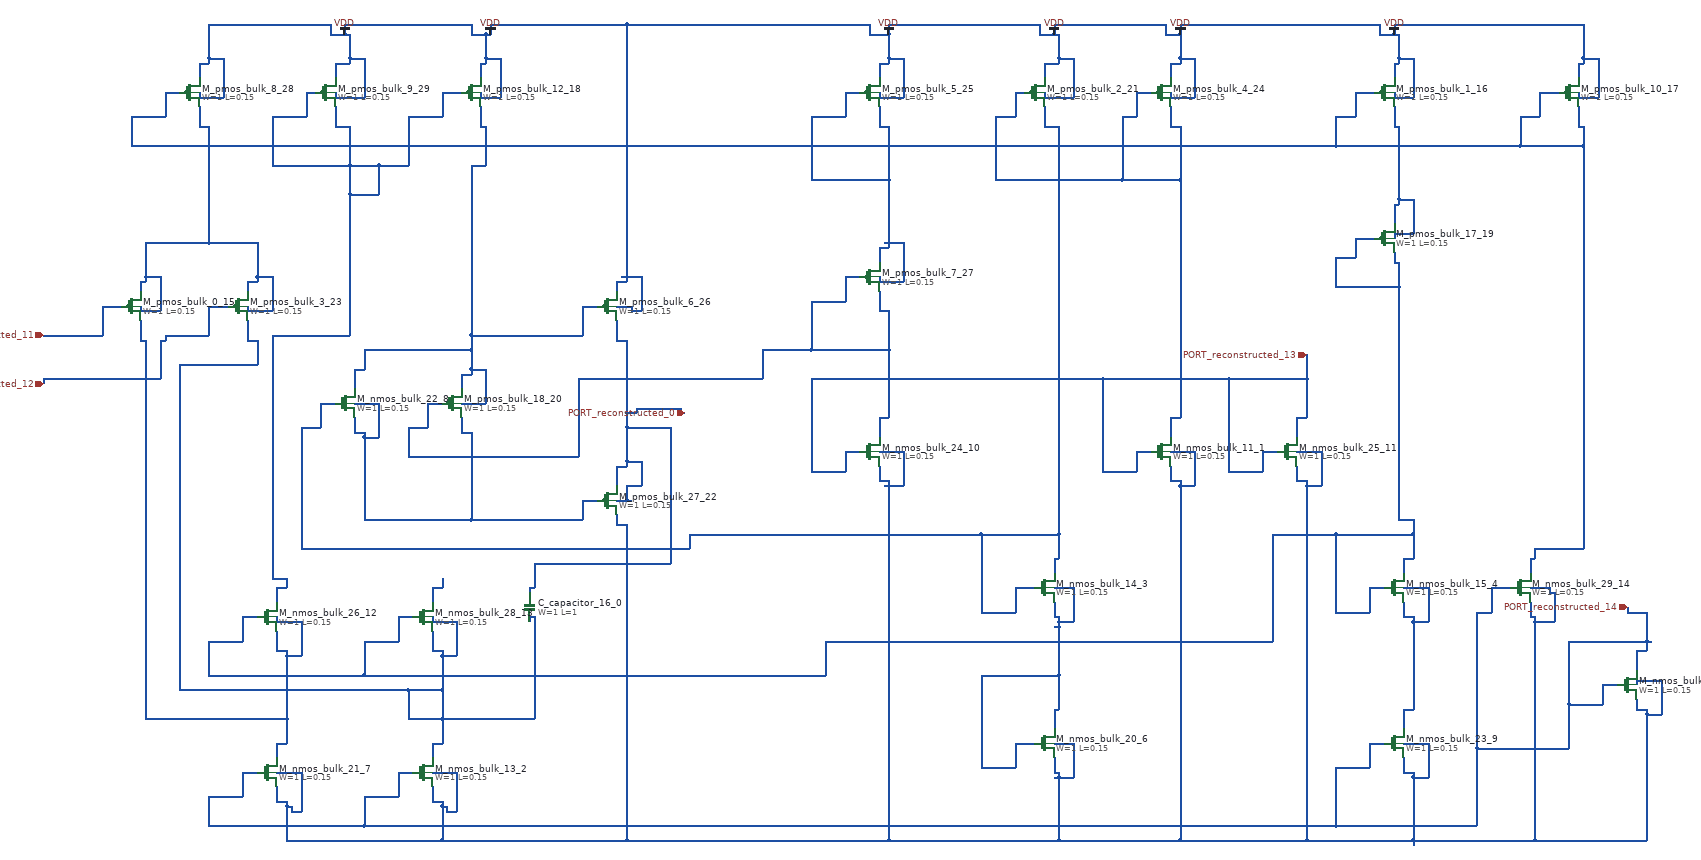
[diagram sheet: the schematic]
v {xschem version=3.4.8 file_version=1.2}
G {}
K {}
V {}
S {}
E {}
C {sky130_fd_pr/cap_mim_m3_1.sym} 1160 1220 2 0 {name="C_capacitor_16_0" model=cap_mim_m3_1 W=1 L=1 MF=1 spiceprefix=X}
C {sky130_fd_pr/nfet_01v8.sym} 2460 900 0 0 {name="M_nmos_bulk_11_1"
W=1
L=0.15
nf=1 
mult=1
ad="expr('int((@nf + 1)/2) * @W / @nf * 0.29')"
pd="expr('2*int((@nf + 1)/2) * (@W / @nf + 0.29)')"
as="expr('int((@nf + 2)/2) * @W / @nf * 0.29')"
ps="expr('2*int((@nf + 2)/2) * (@W / @nf + 0.29)')"
nrd="expr('0.29 / @W ')" nrs="expr('0.29 / @W ')"
sa=0 sb=0 sd=0
model=nfet_01v8
spiceprefix=X
}
C {sky130_fd_pr/nfet_01v8.sym} 940 1560 0 0 {name="M_nmos_bulk_13_2"
W=1
L=0.15
nf=1 
mult=1
ad="expr('int((@nf + 1)/2) * @W / @nf * 0.29')"
pd="expr('2*int((@nf + 1)/2) * (@W / @nf + 0.29)')"
as="expr('int((@nf + 2)/2) * @W / @nf * 0.29')"
ps="expr('2*int((@nf + 2)/2) * (@W / @nf + 0.29)')"
nrd="expr('0.29 / @W ')" nrs="expr('0.29 / @W ')"
sa=0 sb=0 sd=0
model=nfet_01v8
spiceprefix=X
}
C {sky130_fd_pr/nfet_01v8.sym} 2220 1180 0 0 {name="M_nmos_bulk_14_3"
W=1
L=0.15
nf=1 
mult=1
ad="expr('int((@nf + 1)/2) * @W / @nf * 0.29')"
pd="expr('2*int((@nf + 1)/2) * (@W / @nf + 0.29)')"
as="expr('int((@nf + 2)/2) * @W / @nf * 0.29')"
ps="expr('2*int((@nf + 2)/2) * (@W / @nf + 0.29)')"
nrd="expr('0.29 / @W ')" nrs="expr('0.29 / @W ')"
sa=0 sb=0 sd=0
model=nfet_01v8
spiceprefix=X
}
C {sky130_fd_pr/nfet_01v8.sym} 2940 1180 0 0 {name="M_nmos_bulk_15_4"
W=1
L=0.15
nf=1 
mult=1
ad="expr('int((@nf + 1)/2) * @W / @nf * 0.29')"
pd="expr('2*int((@nf + 1)/2) * (@W / @nf + 0.29)')"
as="expr('int((@nf + 2)/2) * @W / @nf * 0.29')"
ps="expr('2*int((@nf + 2)/2) * (@W / @nf + 0.29)')"
nrd="expr('0.29 / @W ')" nrs="expr('0.29 / @W ')"
sa=0 sb=0 sd=0
model=nfet_01v8
spiceprefix=X
}
C {sky130_fd_pr/nfet_01v8.sym} 3420 1380 0 0 {name="M_nmos_bulk_19_5"
W=1
L=0.15
nf=1 
mult=1
ad="expr('int((@nf + 1)/2) * @W / @nf * 0.29')"
pd="expr('2*int((@nf + 1)/2) * (@W / @nf + 0.29)')"
as="expr('int((@nf + 2)/2) * @W / @nf * 0.29')"
ps="expr('2*int((@nf + 2)/2) * (@W / @nf + 0.29)')"
nrd="expr('0.29 / @W ')" nrs="expr('0.29 / @W ')"
sa=0 sb=0 sd=0
model=nfet_01v8
spiceprefix=X
}
C {sky130_fd_pr/nfet_01v8.sym} 2220 1500 0 0 {name="M_nmos_bulk_20_6"
W=1
L=0.15
nf=1 
mult=1
ad="expr('int((@nf + 1)/2) * @W / @nf * 0.29')"
pd="expr('2*int((@nf + 1)/2) * (@W / @nf + 0.29)')"
as="expr('int((@nf + 2)/2) * @W / @nf * 0.29')"
ps="expr('2*int((@nf + 2)/2) * (@W / @nf + 0.29)')"
nrd="expr('0.29 / @W ')" nrs="expr('0.29 / @W ')"
sa=0 sb=0 sd=0
model=nfet_01v8
spiceprefix=X
}
C {sky130_fd_pr/nfet_01v8.sym} 620 1560 0 0 {name="M_nmos_bulk_21_7"
W=1
L=0.15
nf=1 
mult=1
ad="expr('int((@nf + 1)/2) * @W / @nf * 0.29')"
pd="expr('2*int((@nf + 1)/2) * (@W / @nf + 0.29)')"
as="expr('int((@nf + 2)/2) * @W / @nf * 0.29')"
ps="expr('2*int((@nf + 2)/2) * (@W / @nf + 0.29)')"
nrd="expr('0.29 / @W ')" nrs="expr('0.29 / @W ')"
sa=0 sb=0 sd=0
model=nfet_01v8
spiceprefix=X
}
C {sky130_fd_pr/nfet_01v8.sym} 780 800 0 0 {name="M_nmos_bulk_22_8"
W=1
L=0.15
nf=1 
mult=1
ad="expr('int((@nf + 1)/2) * @W / @nf * 0.29')"
pd="expr('2*int((@nf + 1)/2) * (@W / @nf + 0.29)')"
as="expr('int((@nf + 2)/2) * @W / @nf * 0.29')"
ps="expr('2*int((@nf + 2)/2) * (@W / @nf + 0.29)')"
nrd="expr('0.29 / @W ')" nrs="expr('0.29 / @W ')"
sa=0 sb=0 sd=0
model=nfet_01v8
spiceprefix=X
}
C {sky130_fd_pr/nfet_01v8.sym} 2940 1500 0 0 {name="M_nmos_bulk_23_9"
W=1
L=0.15
nf=1 
mult=1
ad="expr('int((@nf + 1)/2) * @W / @nf * 0.29')"
pd="expr('2*int((@nf + 1)/2) * (@W / @nf + 0.29)')"
as="expr('int((@nf + 2)/2) * @W / @nf * 0.29')"
ps="expr('2*int((@nf + 2)/2) * (@W / @nf + 0.29)')"
nrd="expr('0.29 / @W ')" nrs="expr('0.29 / @W ')"
sa=0 sb=0 sd=0
model=nfet_01v8
spiceprefix=X
}
C {sky130_fd_pr/nfet_01v8.sym} 1860 900 0 0 {name="M_nmos_bulk_24_10"
W=1
L=0.15
nf=1 
mult=1
ad="expr('int((@nf + 1)/2) * @W / @nf * 0.29')"
pd="expr('2*int((@nf + 1)/2) * (@W / @nf + 0.29)')"
as="expr('int((@nf + 2)/2) * @W / @nf * 0.29')"
ps="expr('2*int((@nf + 2)/2) * (@W / @nf + 0.29)')"
nrd="expr('0.29 / @W ')" nrs="expr('0.29 / @W ')"
sa=0 sb=0 sd=0
model=nfet_01v8
spiceprefix=X
}
C {sky130_fd_pr/nfet_01v8.sym} 2720 900 0 0 {name="M_nmos_bulk_25_11"
W=1
L=0.15
nf=1 
mult=1
ad="expr('int((@nf + 1)/2) * @W / @nf * 0.29')"
pd="expr('2*int((@nf + 1)/2) * (@W / @nf + 0.29)')"
as="expr('int((@nf + 2)/2) * @W / @nf * 0.29')"
ps="expr('2*int((@nf + 2)/2) * (@W / @nf + 0.29)')"
nrd="expr('0.29 / @W ')" nrs="expr('0.29 / @W ')"
sa=0 sb=0 sd=0
model=nfet_01v8
spiceprefix=X
}
C {sky130_fd_pr/nfet_01v8.sym} 620 1240 0 0 {name="M_nmos_bulk_26_12"
W=1
L=0.15
nf=1 
mult=1
ad="expr('int((@nf + 1)/2) * @W / @nf * 0.29')"
pd="expr('2*int((@nf + 1)/2) * (@W / @nf + 0.29)')"
as="expr('int((@nf + 2)/2) * @W / @nf * 0.29')"
ps="expr('2*int((@nf + 2)/2) * (@W / @nf + 0.29)')"
nrd="expr('0.29 / @W ')" nrs="expr('0.29 / @W ')"
sa=0 sb=0 sd=0
model=nfet_01v8
spiceprefix=X
}
C {sky130_fd_pr/nfet_01v8.sym} 940 1240 0 0 {name="M_nmos_bulk_28_13"
W=1
L=0.15
nf=1 
mult=1
ad="expr('int((@nf + 1)/2) * @W / @nf * 0.29')"
pd="expr('2*int((@nf + 1)/2) * (@W / @nf + 0.29)')"
as="expr('int((@nf + 2)/2) * @W / @nf * 0.29')"
ps="expr('2*int((@nf + 2)/2) * (@W / @nf + 0.29)')"
nrd="expr('0.29 / @W ')" nrs="expr('0.29 / @W ')"
sa=0 sb=0 sd=0
model=nfet_01v8
spiceprefix=X
}
C {sky130_fd_pr/nfet_01v8.sym} 3200 1180 0 0 {name="M_nmos_bulk_29_14"
W=1
L=0.15
nf=1 
mult=1
ad="expr('int((@nf + 1)/2) * @W / @nf * 0.29')"
pd="expr('2*int((@nf + 1)/2) * (@W / @nf + 0.29)')"
as="expr('int((@nf + 2)/2) * @W / @nf * 0.29')"
ps="expr('2*int((@nf + 2)/2) * (@W / @nf + 0.29)')"
nrd="expr('0.29 / @W ')" nrs="expr('0.29 / @W ')"
sa=0 sb=0 sd=0
model=nfet_01v8
spiceprefix=X
}
C {sky130_fd_pr/pfet_01v8.sym} 340 600 0 0 {name="M_pmos_bulk_0_15"
W=1
L=0.15
nf=1
mult=1
ad="expr('int((@nf + 1)/2) * @W / @nf * 0.29')"
pd="expr('2*int((@nf + 1)/2) * (@W / @nf + 0.29)')"
as="expr('int((@nf + 2)/2) * @W / @nf * 0.29')"
ps="expr('2*int((@nf + 2)/2) * (@W / @nf + 0.29)')"
nrd="expr('0.29 / @W ')" nrs="expr('0.29 / @W ')"
sa=0 sb=0 sd=0
model=pfet_01v8
spiceprefix=X
}
C {sky130_fd_pr/pfet_01v8.sym} 2920 160 0 0 {name="M_pmos_bulk_1_16"
W=1
L=0.15
nf=1
mult=1
ad="expr('int((@nf + 1)/2) * @W / @nf * 0.29')"
pd="expr('2*int((@nf + 1)/2) * (@W / @nf + 0.29)')"
as="expr('int((@nf + 2)/2) * @W / @nf * 0.29')"
ps="expr('2*int((@nf + 2)/2) * (@W / @nf + 0.29)')"
nrd="expr('0.29 / @W ')" nrs="expr('0.29 / @W ')"
sa=0 sb=0 sd=0
model=pfet_01v8
spiceprefix=X
}
C {sky130_fd_pr/pfet_01v8.sym} 3300 160 0 0 {name="M_pmos_bulk_10_17"
W=1
L=0.15
nf=1
mult=1
ad="expr('int((@nf + 1)/2) * @W / @nf * 0.29')"
pd="expr('2*int((@nf + 1)/2) * (@W / @nf + 0.29)')"
as="expr('int((@nf + 2)/2) * @W / @nf * 0.29')"
ps="expr('2*int((@nf + 2)/2) * (@W / @nf + 0.29)')"
nrd="expr('0.29 / @W ')" nrs="expr('0.29 / @W ')"
sa=0 sb=0 sd=0
model=pfet_01v8
spiceprefix=X
}
C {sky130_fd_pr/pfet_01v8.sym} 1040 160 0 0 {name="M_pmos_bulk_12_18"
W=1
L=0.15
nf=1
mult=1
ad="expr('int((@nf + 1)/2) * @W / @nf * 0.29')"
pd="expr('2*int((@nf + 1)/2) * (@W / @nf + 0.29)')"
as="expr('int((@nf + 2)/2) * @W / @nf * 0.29')"
ps="expr('2*int((@nf + 2)/2) * (@W / @nf + 0.29)')"
nrd="expr('0.29 / @W ')" nrs="expr('0.29 / @W ')"
sa=0 sb=0 sd=0
model=pfet_01v8
spiceprefix=X
}
C {sky130_fd_pr/pfet_01v8.sym} 2920 460 0 0 {name="M_pmos_bulk_17_19"
W=1
L=0.15
nf=1
mult=1
ad="expr('int((@nf + 1)/2) * @W / @nf * 0.29')"
pd="expr('2*int((@nf + 1)/2) * (@W / @nf + 0.29)')"
as="expr('int((@nf + 2)/2) * @W / @nf * 0.29')"
ps="expr('2*int((@nf + 2)/2) * (@W / @nf + 0.29)')"
nrd="expr('0.29 / @W ')" nrs="expr('0.29 / @W ')"
sa=0 sb=0 sd=0
model=pfet_01v8
spiceprefix=X
}
C {sky130_fd_pr/pfet_01v8.sym} 1000 800 0 0 {name="M_pmos_bulk_18_20"
W=1
L=0.15
nf=1
mult=1
ad="expr('int((@nf + 1)/2) * @W / @nf * 0.29')"
pd="expr('2*int((@nf + 1)/2) * (@W / @nf + 0.29)')"
as="expr('int((@nf + 2)/2) * @W / @nf * 0.29')"
ps="expr('2*int((@nf + 2)/2) * (@W / @nf + 0.29)')"
nrd="expr('0.29 / @W ')" nrs="expr('0.29 / @W ')"
sa=0 sb=0 sd=0
model=pfet_01v8
spiceprefix=X
}
C {sky130_fd_pr/pfet_01v8.sym} 2200 160 0 0 {name="M_pmos_bulk_2_21"
W=1
L=0.15
nf=1
mult=1
ad="expr('int((@nf + 1)/2) * @W / @nf * 0.29')"
pd="expr('2*int((@nf + 1)/2) * (@W / @nf + 0.29)')"
as="expr('int((@nf + 2)/2) * @W / @nf * 0.29')"
ps="expr('2*int((@nf + 2)/2) * (@W / @nf + 0.29)')"
nrd="expr('0.29 / @W ')" nrs="expr('0.29 / @W ')"
sa=0 sb=0 sd=0
model=pfet_01v8
spiceprefix=X
}
C {sky130_fd_pr/pfet_01v8.sym} 1320 1000 0 0 {name="M_pmos_bulk_27_22"
W=1
L=0.15
nf=1
mult=1
ad="expr('int((@nf + 1)/2) * @W / @nf * 0.29')"
pd="expr('2*int((@nf + 1)/2) * (@W / @nf + 0.29)')"
as="expr('int((@nf + 2)/2) * @W / @nf * 0.29')"
ps="expr('2*int((@nf + 2)/2) * (@W / @nf + 0.29)')"
nrd="expr('0.29 / @W ')" nrs="expr('0.29 / @W ')"
sa=0 sb=0 sd=0
model=pfet_01v8
spiceprefix=X
}
C {sky130_fd_pr/pfet_01v8.sym} 560 600 0 0 {name="M_pmos_bulk_3_23"
W=1
L=0.15
nf=1
mult=1
ad="expr('int((@nf + 1)/2) * @W / @nf * 0.29')"
pd="expr('2*int((@nf + 1)/2) * (@W / @nf + 0.29)')"
as="expr('int((@nf + 2)/2) * @W / @nf * 0.29')"
ps="expr('2*int((@nf + 2)/2) * (@W / @nf + 0.29)')"
nrd="expr('0.29 / @W ')" nrs="expr('0.29 / @W ')"
sa=0 sb=0 sd=0
model=pfet_01v8
spiceprefix=X
}
C {sky130_fd_pr/pfet_01v8.sym} 2460 160 0 0 {name="M_pmos_bulk_4_24"
W=1
L=0.15
nf=1
mult=1
ad="expr('int((@nf + 1)/2) * @W / @nf * 0.29')"
pd="expr('2*int((@nf + 1)/2) * (@W / @nf + 0.29)')"
as="expr('int((@nf + 2)/2) * @W / @nf * 0.29')"
ps="expr('2*int((@nf + 2)/2) * (@W / @nf + 0.29)')"
nrd="expr('0.29 / @W ')" nrs="expr('0.29 / @W ')"
sa=0 sb=0 sd=0
model=pfet_01v8
spiceprefix=X
}
C {sky130_fd_pr/pfet_01v8.sym} 1860 160 0 0 {name="M_pmos_bulk_5_25"
W=1
L=0.15
nf=1
mult=1
ad="expr('int((@nf + 1)/2) * @W / @nf * 0.29')"
pd="expr('2*int((@nf + 1)/2) * (@W / @nf + 0.29)')"
as="expr('int((@nf + 2)/2) * @W / @nf * 0.29')"
ps="expr('2*int((@nf + 2)/2) * (@W / @nf + 0.29)')"
nrd="expr('0.29 / @W ')" nrs="expr('0.29 / @W ')"
sa=0 sb=0 sd=0
model=pfet_01v8
spiceprefix=X
}
C {sky130_fd_pr/pfet_01v8.sym} 1320 600 0 0 {name="M_pmos_bulk_6_26"
W=1
L=0.15
nf=1
mult=1
ad="expr('int((@nf + 1)/2) * @W / @nf * 0.29')"
pd="expr('2*int((@nf + 1)/2) * (@W / @nf + 0.29)')"
as="expr('int((@nf + 2)/2) * @W / @nf * 0.29')"
ps="expr('2*int((@nf + 2)/2) * (@W / @nf + 0.29)')"
nrd="expr('0.29 / @W ')" nrs="expr('0.29 / @W ')"
sa=0 sb=0 sd=0
model=pfet_01v8
spiceprefix=X
}
C {sky130_fd_pr/pfet_01v8.sym} 1860 540 0 0 {name="M_pmos_bulk_7_27"
W=1
L=0.15
nf=1
mult=1
ad="expr('int((@nf + 1)/2) * @W / @nf * 0.29')"
pd="expr('2*int((@nf + 1)/2) * (@W / @nf + 0.29)')"
as="expr('int((@nf + 2)/2) * @W / @nf * 0.29')"
ps="expr('2*int((@nf + 2)/2) * (@W / @nf + 0.29)')"
nrd="expr('0.29 / @W ')" nrs="expr('0.29 / @W ')"
sa=0 sb=0 sd=0
model=pfet_01v8
spiceprefix=X
}
C {sky130_fd_pr/pfet_01v8.sym} 460 160 0 0 {name="M_pmos_bulk_8_28"
W=1
L=0.15
nf=1
mult=1
ad="expr('int((@nf + 1)/2) * @W / @nf * 0.29')"
pd="expr('2*int((@nf + 1)/2) * (@W / @nf + 0.29)')"
as="expr('int((@nf + 2)/2) * @W / @nf * 0.29')"
ps="expr('2*int((@nf + 2)/2) * (@W / @nf + 0.29)')"
nrd="expr('0.29 / @W ')" nrs="expr('0.29 / @W ')"
sa=0 sb=0 sd=0
model=pfet_01v8
spiceprefix=X
}
C {sky130_fd_pr/pfet_01v8.sym} 740 160 0 0 {name="M_pmos_bulk_9_29"
W=1
L=0.15
nf=1
mult=1
ad="expr('int((@nf + 1)/2) * @W / @nf * 0.29')"
pd="expr('2*int((@nf + 1)/2) * (@W / @nf + 0.29)')"
as="expr('int((@nf + 2)/2) * @W / @nf * 0.29')"
ps="expr('2*int((@nf + 2)/2) * (@W / @nf + 0.29)')"
nrd="expr('0.29 / @W ')" nrs="expr('0.29 / @W ')"
sa=0 sb=0 sd=0
model=pfet_01v8
spiceprefix=X
}
C {devices/ipin.sym} 160 660 0 0 {name="p_port_30_30" lab="PORT_reconstructed_11"}
C {devices/ipin.sym} 160 760 0 0 {name="p_port_31_31" lab="PORT_reconstructed_12"}
C {devices/ipin.sym} 1480 820 0 0 {name="p_port_32_32" lab="PORT_reconstructed_0"}
C {devices/ipin.sym} 2760 700 0 0 {name="p_port_33_33" lab="PORT_reconstructed_13"}
C {devices/ipin.sym} 3420 1220 0 0 {name="p_port_37_34" lab="PORT_reconstructed_14"}
C {devices/vdd.sym} 2500 40 0 0 {name="l_vdd_34_35" lab="VDD"}
C {devices/vdd.sym} 1900 40 0 0 {name="l_vdd_35_36" lab="VDD"}
C {devices/vdd.sym} 2240 40 0 0 {name="l_vdd_36_37" lab="VDD"}
C {devices/vdd.sym} 1080 40 0 0 {name="l_vdd_38_38" lab="VDD"}
C {devices/vdd.sym} 780 40 0 0 {name="l_vdd_39_39" lab="VDD"}
C {devices/vdd.sym} 2940 40 0 0 {name="l_vdd_40_40" lab="VDD"}
N 1160 1180 1170 1180 {}
N 1170 1130 1450 1130 {}
N 1340 1000 1360 1000 {}
N 1360 1000 1370 1000 {}
N 1360 970 1390 970 {}
N 1340 930 1360 930 {}
N 1360 920 1390 920 {}
N 1360 850 1450 850 {}
N 1360 820 1380 820 {}
N 1470 820 1480 820 {}
N 1380 810 1470 810 {}
N 1340 670 1360 670 {}
N 1160 1190 1160 1180 {}
N 1170 1180 1170 1130 {}
N 1340 970 1340 930 {}
N 1340 670 1340 630 {}
N 1360 1000 1360 970 {}
N 1360 930 1360 920 {}
N 1360 920 1360 850 {}
N 1360 850 1360 820 {}
N 1360 820 1360 670 {}
N 1380 820 1380 810 {}
N 1390 970 1390 920 {}
N 1450 1130 1450 850 {}
N 1470 820 1470 810 {}
N 960 1500 980 1500 {}
N 910 1450 980 1450 {}
N 980 1450 1170 1450 {}
N 440 1390 910 1390 {}
N 910 1390 980 1390 {}
N 980 1320 1010 1320 {}
N 960 1310 980 1310 {}
N 960 1250 1010 1250 {}
N 1160 1240 1170 1240 {}
N 440 720 600 720 {}
N 580 670 600 670 {}
N 440 1390 440 720 {}
N 580 670 580 630 {}
N 600 720 600 670 {}
N 910 1450 910 1390 {}
N 960 1530 960 1500 {}
N 960 1310 960 1270 {}
N 960 1250 960 1240 {}
N 980 1500 980 1450 {}
N 980 1450 980 1390 {}
N 980 1390 980 1320 {}
N 980 1320 980 1310 {}
N 1010 1320 1010 1250 {}
N 1160 1250 1160 1240 {}
N 1170 1450 1170 1240 {}
N 640 1180 660 1180 {}
N 630 1160 660 1160 {}
N 630 660 790 660 {}
N 790 370 850 370 {}
N 630 310 790 310 {}
N 790 310 850 310 {}
N 850 310 910 310 {}
N 760 230 790 230 {}
N 630 210 700 210 {}
N 910 210 980 210 {}
N 700 160 720 160 {}
N 980 160 1020 160 {}
N 630 1160 630 660 {}
N 630 310 630 210 {}
N 640 1210 640 1180 {}
N 660 1180 660 1160 {}
N 700 210 700 160 {}
N 760 230 760 190 {}
N 790 660 790 370 {}
N 790 370 790 310 {}
N 790 310 790 230 {}
N 850 370 850 310 {}
N 910 310 910 210 {}
N 980 210 980 160 {}
N 160 660 280 660 {}
N 280 600 320 600 {}
N 280 660 280 600 {}
N 160 750 400 750 {}
N 400 670 410 670 {}
N 410 660 500 660 {}
N 500 600 540 600 {}
N 160 760 160 750 {}
N 400 750 400 670 {}
N 410 670 410 660 {}
N 500 660 500 600 {}
N 1740 940 1810 940 {}
N 2340 940 2410 940 {}
N 2600 940 2670 940 {}
N 1810 900 1840 900 {}
N 2410 900 2440 900 {}
N 2670 900 2700 900 {}
N 2740 830 2760 830 {}
N 1740 750 2340 750 {}
N 2340 750 2600 750 {}
N 2600 750 2760 750 {}
N 1740 940 1740 750 {}
N 1810 940 1810 900 {}
N 2340 940 2340 750 {}
N 2410 940 2410 900 {}
N 2600 940 2600 750 {}
N 2670 940 2670 900 {}
N 2740 870 2740 830 {}
N 2760 830 2760 750 {}
N 2760 750 2760 700 {}
N 500 1670 820 1670 {}
N 820 1670 2820 1670 {}
N 2820 1670 3110 1670 {}
N 500 1610 570 1610 {}
N 820 1610 890 1610 {}
N 570 1560 600 1560 {}
N 890 1560 920 1560 {}
N 2820 1550 2890 1550 {}
N 3110 1510 3300 1510 {}
N 2890 1500 2920 1500 {}
N 3300 1420 3370 1420 {}
N 3370 1380 3400 1380 {}
N 3440 1310 3460 1310 {}
N 3300 1290 3460 1290 {}
N 3460 1290 3470 1290 {}
N 3110 1230 3140 1230 {}
N 3420 1230 3460 1230 {}
N 3140 1180 3180 1180 {}
N 500 1670 500 1610 {}
N 570 1610 570 1560 {}
N 820 1670 820 1610 {}
N 890 1610 890 1560 {}
N 2820 1670 2820 1550 {}
N 2890 1550 2890 1500 {}
N 3110 1670 3110 1510 {}
N 3110 1510 3110 1230 {}
N 3140 1230 3140 1180 {}
N 3300 1510 3300 1420 {}
N 3300 1420 3300 1290 {}
N 3370 1420 3370 1380 {}
N 3420 1230 3420 1220 {}
N 3440 1350 3440 1310 {}
N 3460 1310 3460 1290 {}
N 3460 1290 3460 1230 {}
N 2960 1430 2980 1430 {}
N 2980 1250 3010 1250 {}
N 2960 1240 2980 1240 {}
N 2960 1180 3010 1180 {}
N 2960 1470 2960 1430 {}
N 2960 1240 2960 1210 {}
N 2980 1430 2980 1250 {}
N 2980 1250 2980 1240 {}
N 3010 1250 3010 1180 {}
N 500 1360 820 1360 {}
N 820 1360 1770 1360 {}
N 500 1290 570 1290 {}
N 820 1290 890 1290 {}
N 1770 1290 2690 1290 {}
N 570 1240 600 1240 {}
N 890 1240 920 1240 {}
N 2820 1230 2890 1230 {}
N 2890 1180 2920 1180 {}
N 2960 1120 2980 1120 {}
N 2690 1070 2820 1070 {}
N 2820 1070 2980 1070 {}
N 2950 1040 2980 1040 {}
N 2820 560 2950 560 {}
N 2940 510 2950 510 {}
N 2820 500 2860 500 {}
N 2860 460 2900 460 {}
N 500 1360 500 1290 {}
N 570 1290 570 1240 {}
N 820 1360 820 1290 {}
N 890 1290 890 1240 {}
N 1770 1360 1770 1290 {}
N 2690 1290 2690 1070 {}
N 2820 1230 2820 1070 {}
N 2820 560 2820 500 {}
N 2860 500 2860 460 {}
N 2890 1230 2890 1180 {}
N 2940 510 2940 490 {}
N 2950 1040 2950 560 {}
N 2950 560 2950 510 {}
N 2960 1150 2960 1120 {}
N 2980 1120 2980 1070 {}
N 2980 1070 2980 1040 {}
N 660 1700 980 1700 {}
N 980 1700 1360 1700 {}
N 1360 1700 1900 1700 {}
N 1900 1700 2250 1700 {}
N 2250 1700 2500 1700 {}
N 2500 1700 2760 1700 {}
N 2760 1700 2980 1700 {}
N 2980 1700 3230 1700 {}
N 3230 1700 3460 1700 {}
N 670 1640 690 1640 {}
N 990 1640 1010 1640 {}
N 660 1630 670 1630 {}
N 980 1630 990 1630 {}
N 640 1620 660 1620 {}
N 960 1620 980 1620 {}
N 2240 1570 2250 1570 {}
N 2250 1570 2280 1570 {}
N 2980 1570 3010 1570 {}
N 640 1560 690 1560 {}
N 960 1560 1010 1560 {}
N 2240 1560 2250 1560 {}
N 2960 1560 2980 1560 {}
N 2240 1500 2280 1500 {}
N 2960 1500 3010 1500 {}
N 3460 1440 3490 1440 {}
N 3440 1430 3460 1430 {}
N 3440 1370 3490 1370 {}
N 3230 1250 3270 1250 {}
N 3220 1240 3230 1240 {}
N 3260 1190 3270 1190 {}
N 3220 1180 3260 1180 {}
N 1340 1050 1360 1050 {}
N 1890 970 1900 970 {}
N 1900 970 1930 970 {}
N 2500 970 2530 970 {}
N 2760 970 2790 970 {}
N 1880 960 1900 960 {}
N 2480 960 2500 960 {}
N 2740 960 2760 960 {}
N 1880 900 1930 900 {}
N 2480 900 2530 900 {}
N 2740 900 2790 900 {}
N 640 1620 640 1590 {}
N 660 1700 660 1630 {}
N 660 1630 660 1620 {}
N 670 1640 670 1630 {}
N 690 1640 690 1560 {}
N 960 1620 960 1590 {}
N 980 1700 980 1630 {}
N 980 1630 980 1620 {}
N 990 1640 990 1630 {}
N 1010 1640 1010 1560 {}
N 1340 1050 1340 1030 {}
N 1360 1700 1360 1050 {}
N 1880 960 1880 930 {}
N 1900 1700 1900 970 {}
N 1900 970 1900 960 {}
N 1930 970 1930 900 {}
N 2240 1560 2240 1530 {}
N 2250 1700 2250 1570 {}
N 2250 1570 2250 1560 {}
N 2280 1570 2280 1500 {}
N 2480 960 2480 930 {}
N 2500 1700 2500 970 {}
N 2500 970 2500 960 {}
N 2530 970 2530 900 {}
N 2740 960 2740 930 {}
N 2760 1700 2760 970 {}
N 2760 970 2760 960 {}
N 2790 970 2790 900 {}
N 2960 1560 2960 1530 {}
N 2980 1710 2980 1700 {}
N 2980 1700 2980 1570 {}
N 2980 1570 2980 1560 {}
N 3010 1570 3010 1500 {}
N 3220 1240 3220 1210 {}
N 3230 1700 3230 1250 {}
N 3230 1250 3230 1240 {}
N 3260 1190 3260 1180 {}
N 3270 1250 3270 1190 {}
N 3440 1430 3440 1410 {}
N 3440 1380 3440 1370 {}
N 3460 1700 3460 1440 {}
N 3460 1440 3460 1430 {}
N 3490 1440 3490 1370 {}
N 640 1500 660 1500 {}
N 370 1450 660 1450 {}
N 660 1320 690 1320 {}
N 640 1310 660 1310 {}
N 640 1250 690 1250 {}
N 360 670 370 670 {}
N 360 670 360 630 {}
N 370 1450 370 670 {}
N 640 1530 640 1500 {}
N 640 1310 640 1270 {}
N 640 1250 640 1240 {}
N 660 1500 660 1450 {}
N 660 1450 660 1320 {}
N 660 1320 660 1310 {}
N 690 1320 690 1250 {}
N 2480 830 2500 830 {}
N 2120 340 2380 340 {}
N 2380 340 2500 340 {}
N 2480 230 2500 230 {}
N 2120 210 2160 210 {}
N 2380 210 2410 210 {}
N 2160 160 2180 160 {}
N 2410 160 2440 160 {}
N 2120 340 2120 210 {}
N 2160 210 2160 160 {}
N 2380 340 2380 210 {}
N 2410 210 2410 160 {}
N 2480 870 2480 830 {}
N 2480 230 2480 190 {}
N 2500 830 2500 340 {}
N 2500 340 2500 230 {}
N 2090 1550 2160 1550 {}
N 2160 1500 2200 1500 {}
N 2240 1430 2250 1430 {}
N 2090 1360 2250 1360 {}
N 2240 1260 2250 1260 {}
N 2250 1250 2280 1250 {}
N 2240 1240 2250 1240 {}
N 2240 1180 2280 1180 {}
N 2090 1550 2090 1360 {}
N 2160 1550 2160 1500 {}
N 2240 1470 2240 1430 {}
N 2240 1240 2240 1210 {}
N 2250 1430 2250 1360 {}
N 2250 1360 2250 1260 {}
N 2250 1260 2250 1250 {}
N 2250 1250 2250 1240 {}
N 2280 1250 2280 1180 {}
N 820 1040 1040 1040 {}
N 1040 1040 1270 1040 {}
N 1270 1000 1300 1000 {}
N 820 870 850 870 {}
N 800 860 820 860 {}
N 1020 860 1040 860 {}
N 800 800 850 800 {}
N 800 860 800 830 {}
N 820 1040 820 870 {}
N 820 870 820 860 {}
N 850 870 850 800 {}
N 1020 860 1020 830 {}
N 1040 1040 1040 860 {}
N 1270 1040 1270 1000 {}
N 960 1180 980 1180 {}
N 960 1210 960 1180 {}
N 980 1180 980 1160 {}
N 2940 450 2980 450 {}
N 2940 390 2950 390 {}
N 2950 380 2980 380 {}
N 2940 230 2950 230 {}
N 2940 460 2940 450 {}
N 2940 430 2940 390 {}
N 2940 230 2940 190 {}
N 2950 390 2950 380 {}
N 2950 380 2950 230 {}
N 2980 450 2980 380 {}
N 1880 550 1930 550 {}
N 1880 480 1900 480 {}
N 1890 470 1900 470 {}
N 1900 470 1930 470 {}
N 1740 340 1900 340 {}
N 1880 230 1900 230 {}
N 1740 210 1810 210 {}
N 1810 160 1840 160 {}
N 1740 340 1740 210 {}
N 1810 210 1810 160 {}
N 1880 550 1880 540 {}
N 1880 510 1880 480 {}
N 1880 230 1880 190 {}
N 1900 480 1900 470 {}
N 1900 470 1900 340 {}
N 1900 340 1900 230 {}
N 1930 550 1930 470 {}
N 1370 610 1390 610 {}
N 1340 600 1370 600 {}
N 1340 550 1360 550 {}
N 1350 540 1360 540 {}
N 1360 540 1390 540 {}
N 480 170 530 170 {}
N 760 170 820 170 {}
N 1060 170 1100 170 {}
N 1880 170 1930 170 {}
N 2220 170 2280 170 {}
N 2480 170 2530 170 {}
N 2940 170 2980 170 {}
N 3320 170 3360 170 {}
N 480 100 500 100 {}
N 760 100 790 100 {}
N 1060 100 1070 100 {}
N 1880 100 1900 100 {}
N 2220 100 2250 100 {}
N 2480 100 2500 100 {}
N 2940 100 2950 100 {}
N 3320 100 3330 100 {}
N 500 90 530 90 {}
N 790 90 820 90 {}
N 1070 90 1100 90 {}
N 1900 90 1930 90 {}
N 2250 90 2280 90 {}
N 2500 90 2530 90 {}
N 2950 90 2980 90 {}
N 3330 90 3360 90 {}
N 750 40 780 40 {}
N 780 40 790 40 {}
N 1040 40 1070 40 {}
N 1070 40 1080 40 {}
N 1860 40 1900 40 {}
N 2210 40 2240 40 {}
N 2240 40 2250 40 {}
N 2470 40 2500 40 {}
N 2910 40 2940 40 {}
N 2940 40 2950 40 {}
N 500 20 750 20 {}
N 780 20 1040 20 {}
N 1080 20 1360 20 {}
N 1360 20 1860 20 {}
N 1900 20 2210 20 {}
N 2240 20 2470 20 {}
N 2500 20 2910 20 {}
N 2940 20 3330 20 {}
N 480 170 480 160 {}
N 480 130 480 100 {}
N 500 100 500 90 {}
N 500 90 500 20 {}
N 530 170 530 90 {}
N 750 40 750 20 {}
N 760 170 760 160 {}
N 760 130 760 100 {}
N 780 40 780 20 {}
N 790 100 790 90 {}
N 790 90 790 40 {}
N 820 170 820 90 {}
N 1040 40 1040 20 {}
N 1060 170 1060 160 {}
N 1060 130 1060 100 {}
N 1070 100 1070 90 {}
N 1070 90 1070 40 {}
N 1080 40 1080 20 {}
N 1100 170 1100 90 {}
N 1340 570 1340 550 {}
N 1360 550 1360 540 {}
N 1360 540 1360 20 {}
N 1370 610 1370 600 {}
N 1390 610 1390 540 {}
N 1860 40 1860 20 {}
N 1880 170 1880 160 {}
N 1880 130 1880 100 {}
N 1900 100 1900 90 {}
N 1900 90 1900 40 {}
N 1900 40 1900 20 {}
N 1930 170 1930 90 {}
N 2210 40 2210 20 {}
N 2220 170 2220 160 {}
N 2220 130 2220 100 {}
N 2240 40 2240 20 {}
N 2250 100 2250 90 {}
N 2250 90 2250 40 {}
N 2280 170 2280 90 {}
N 2470 40 2470 20 {}
N 2480 170 2480 160 {}
N 2480 130 2480 100 {}
N 2500 100 2500 90 {}
N 2500 90 2500 40 {}
N 2500 40 2500 20 {}
N 2530 170 2530 90 {}
N 2910 40 2910 20 {}
N 2940 170 2940 160 {}
N 2940 130 2940 100 {}
N 2940 40 2940 20 {}
N 2950 100 2950 90 {}
N 2950 90 2950 40 {}
N 2980 170 2980 90 {}
N 3320 170 3320 160 {}
N 3320 130 3320 100 {}
N 3330 100 3330 90 {}
N 3330 90 3330 20 {}
N 3360 170 3360 90 {}
N 1020 800 1070 800 {}
N 1020 740 1040 740 {}
N 800 730 820 730 {}
N 1040 730 1070 730 {}
N 820 690 1040 690 {}
N 1040 660 1270 660 {}
N 1270 600 1300 600 {}
N 1040 310 1070 310 {}
N 1060 230 1070 230 {}
N 800 770 800 730 {}
N 820 730 820 690 {}
N 1020 770 1020 740 {}
N 1040 740 1040 730 {}
N 1040 730 1040 690 {}
N 1040 690 1040 660 {}
N 1040 660 1040 310 {}
N 1060 230 1060 190 {}
N 1070 800 1070 730 {}
N 1070 310 1070 230 {}
N 1270 660 1270 600 {}
N 910 910 1260 910 {}
N 910 850 950 850 {}
N 1880 830 1900 830 {}
N 950 800 980 800 {}
N 1260 750 1640 750 {}
N 1640 690 1740 690 {}
N 1740 690 1900 690 {}
N 1880 610 1900 610 {}
N 1740 590 1810 590 {}
N 1810 540 1840 540 {}
N 910 910 910 850 {}
N 950 850 950 800 {}
N 1260 910 1260 750 {}
N 1640 750 1640 690 {}
N 1740 690 1740 590 {}
N 1810 590 1810 540 {}
N 1880 870 1880 830 {}
N 1880 610 1880 570 {}
N 1900 830 1900 690 {}
N 1900 690 1900 610 {}
N 2090 1230 2160 1230 {}
N 2160 1180 2200 1180 {}
N 2240 1120 2250 1120 {}
N 690 1100 1490 1100 {}
N 1490 1070 2090 1070 {}
N 2090 1070 2250 1070 {}
N 690 850 730 850 {}
N 730 800 760 800 {}
N 2220 230 2250 230 {}
N 690 1100 690 850 {}
N 730 850 730 800 {}
N 1490 1100 1490 1070 {}
N 2090 1230 2090 1070 {}
N 2160 1230 2160 1180 {}
N 2220 230 2220 190 {}
N 2240 1150 2240 1120 {}
N 2250 1120 2250 1070 {}
N 2250 1070 2250 230 {}
N 360 610 400 610 {}
N 580 610 630 610 {}
N 360 550 370 550 {}
N 580 550 600 550 {}
N 370 540 400 540 {}
N 600 540 630 540 {}
N 370 470 500 470 {}
N 500 470 600 470 {}
N 480 230 500 230 {}
N 360 610 360 600 {}
N 360 570 360 550 {}
N 370 550 370 540 {}
N 370 540 370 470 {}
N 400 610 400 540 {}
N 480 230 480 190 {}
N 500 470 500 230 {}
N 580 610 580 600 {}
N 580 570 580 550 {}
N 600 550 600 540 {}
N 600 540 600 470 {}
N 630 610 630 540 {}
N 3220 1120 3230 1120 {}
N 3230 1100 3330 1100 {}
N 340 270 2820 270 {}
N 2820 270 3200 270 {}
N 3200 270 3330 270 {}
N 3320 230 3330 230 {}
N 340 210 410 210 {}
N 2820 210 2860 210 {}
N 3200 210 3240 210 {}
N 410 160 440 160 {}
N 2860 160 2900 160 {}
N 3240 160 3280 160 {}
N 340 270 340 210 {}
N 410 210 410 160 {}
N 2820 270 2820 210 {}
N 2860 210 2860 160 {}
N 3200 270 3200 210 {}
N 3220 1150 3220 1120 {}
N 3230 1120 3230 1100 {}
N 3240 210 3240 160 {}
N 3320 230 3320 190 {}
N 3330 1100 3330 270 {}
N 3330 270 3330 230 {}
